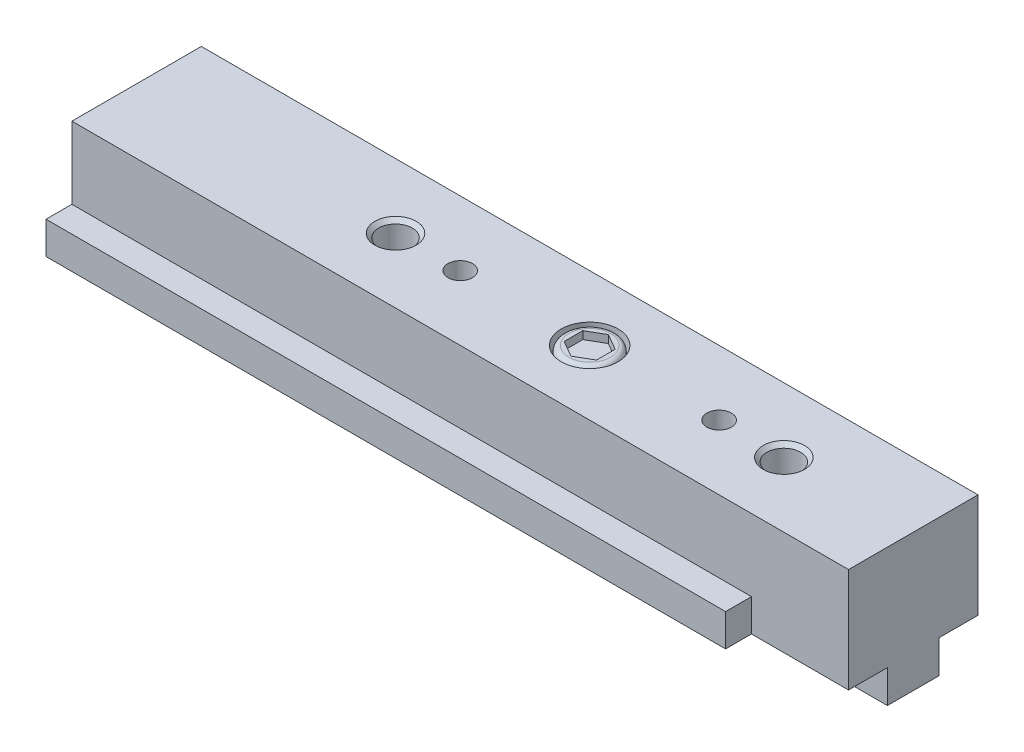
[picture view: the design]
ISO-10303-21;
HEADER;
FILE_DESCRIPTION(('STEP AP214'),'2;1');
FILE_NAME('part.step','',(''),(''),'','','');
FILE_SCHEMA(('AUTOMOTIVE_DESIGN { 1 0 10303 214 1 1 1 1 }'));
ENDSEC;
DATA;
#1=APPLICATION_CONTEXT('core data for automotive mechanical design processes');
#2=APPLICATION_PROTOCOL_DEFINITION('international standard','automotive_design',2000,#1);
#3=PRODUCT_CONTEXT('',#1,'mechanical');
#4=PRODUCT('Part','Part','',(#3));
#5=PRODUCT_RELATED_PRODUCT_CATEGORY('part','',(#4));
#6=PRODUCT_DEFINITION_FORMATION('','',#4);
#7=PRODUCT_DEFINITION_CONTEXT('part definition',#1,'design');
#8=PRODUCT_DEFINITION('design','',#6,#7);
#9=PRODUCT_DEFINITION_SHAPE('','',#8);
#10=(LENGTH_UNIT() NAMED_UNIT(*) SI_UNIT(.MILLI.,.METRE.));
#11=(NAMED_UNIT(*) PLANE_ANGLE_UNIT() SI_UNIT($,.RADIAN.));
#12=(NAMED_UNIT(*) SI_UNIT($,.STERADIAN.) SOLID_ANGLE_UNIT());
#13=UNCERTAINTY_MEASURE_WITH_UNIT(LENGTH_MEASURE(1.E-05),#10,'distance_accuracy_value','');
#14=(GEOMETRIC_REPRESENTATION_CONTEXT(3) GLOBAL_UNCERTAINTY_ASSIGNED_CONTEXT((#13)) GLOBAL_UNIT_ASSIGNED_CONTEXT((#10,
#11,#12)) REPRESENTATION_CONTEXT('',''));
#15=CARTESIAN_POINT('',(0.,0.,0.));
#16=DIRECTION('',(0.,0.,1.));
#17=DIRECTION('',(1.,0.,0.));
#18=AXIS2_PLACEMENT_3D('',#15,#16,#17);
#19=CARTESIAN_POINT('',(44.45,11.938,0.));
#20=DIRECTION('',(0.,1.,0.));
#21=DIRECTION('',(0.,0.,1.));
#22=AXIS2_PLACEMENT_3D('',#19,#20,#21);
#23=PLANE('',#22);
#24=CARTESIAN_POINT('',(44.45,11.938,0.));
#25=DIRECTION('',(0.,1.,0.));
#26=DIRECTION('',(0.,0.,1.));
#27=AXIS2_PLACEMENT_3D('',#24,#25,#26);
#28=CIRCLE('',#27,2.794);
#29=CARTESIAN_POINT('',(44.45,11.938,2.794));
#30=VERTEX_POINT('',#29);
#31=EDGE_CURVE('E242',#30,#30,#28,.T.);
#32=ORIENTED_EDGE('',*,*,#31,.T.);
#33=EDGE_LOOP('',(#32));
#34=FACE_BOUND('',#33,.T.);
#35=CARTESIAN_POINT('',(44.45,11.938,0.));
#36=DIRECTION('',(0.,1.,0.));
#37=DIRECTION('',(0.,0.,1.));
#38=AXIS2_PLACEMENT_3D('',#35,#36,#37);
#39=CIRCLE('',#38,2.54);
#40=CARTESIAN_POINT('',(44.45,11.938,2.54));
#41=VERTEX_POINT('',#40);
#42=EDGE_CURVE('E225',#41,#41,#39,.T.);
#43=ORIENTED_EDGE('',*,*,#42,.F.);
#44=EDGE_LOOP('',(#43));
#45=FACE_BOUND('',#44,.T.);
#46=ADVANCED_FACE('F33',(#34,#45),#23,.T.);
#47=CARTESIAN_POINT('',(66.675,13.462,-6.35));
#48=DIRECTION('',(0.,-1.,0.));
#49=DIRECTION('',(0.,0.,-1.));
#50=AXIS2_PLACEMENT_3D('',#47,#48,#49);
#51=PLANE('',#50);
#52=CARTESIAN_POINT('',(44.45,13.462,0.));
#53=DIRECTION('',(0.,1.,0.));
#54=DIRECTION('',(0.,0.,1.));
#55=AXIS2_PLACEMENT_3D('',#52,#53,#54);
#56=CIRCLE('',#55,2.794);
#57=CARTESIAN_POINT('',(44.45,13.462,2.794));
#58=VERTEX_POINT('',#57);
#59=EDGE_CURVE('E241',#58,#58,#56,.T.);
#60=ORIENTED_EDGE('',*,*,#59,.F.);
#61=EDGE_LOOP('',(#60));
#62=FACE_BOUND('',#61,.T.);
#63=CARTESIAN_POINT('',(31.75,13.462,0.));
#64=DIRECTION('',(0.,1.,0.));
#65=DIRECTION('',(0.,0.,1.));
#66=AXIS2_PLACEMENT_3D('',#63,#64,#65);
#67=CIRCLE('',#66,1.20269);
#68=CARTESIAN_POINT('',(31.75,13.462,1.20269));
#69=VERTEX_POINT('',#68);
#70=EDGE_CURVE('E245',#69,#69,#67,.T.);
#71=ORIENTED_EDGE('',*,*,#70,.F.);
#72=EDGE_LOOP('',(#71));
#73=FACE_BOUND('',#72,.T.);
#74=CARTESIAN_POINT('',(57.15,13.462,0.));
#75=DIRECTION('',(0.,1.,0.));
#76=DIRECTION('',(0.,0.,1.));
#77=AXIS2_PLACEMENT_3D('',#74,#75,#76);
#78=CIRCLE('',#77,1.20269);
#79=CARTESIAN_POINT('',(57.15,13.462,1.20269));
#80=VERTEX_POINT('',#79);
#81=EDGE_CURVE('E251',#80,#80,#78,.T.);
#82=ORIENTED_EDGE('',*,*,#81,.F.);
#83=EDGE_LOOP('',(#82));
#84=FACE_BOUND('',#83,.T.);
#85=CARTESIAN_POINT('',(63.5,13.462,0.));
#86=DIRECTION('',(0.,1.,0.));
#87=DIRECTION('',(0.,0.,1.));
#88=AXIS2_PLACEMENT_3D('',#85,#86,#87);
#89=CIRCLE('',#88,2.032);
#90=CARTESIAN_POINT('',(63.5,13.462,2.032));
#91=VERTEX_POINT('',#90);
#92=EDGE_CURVE('E274',#91,#91,#89,.T.);
#93=ORIENTED_EDGE('',*,*,#92,.F.);
#94=EDGE_LOOP('',(#93));
#95=FACE_BOUND('',#94,.T.);
#96=DIRECTION('',(0.,0.,1.));
#97=VECTOR('',#96,1.);
#98=CARTESIAN_POINT('',(0.,13.462,-6.35));
#99=LINE('',#98,#97);
#100=CARTESIAN_POINT('',(0.,13.462,-6.35));
#101=VERTEX_POINT('',#100);
#102=CARTESIAN_POINT('',(0.,13.462,6.35));
#103=VERTEX_POINT('',#102);
#104=EDGE_CURVE('E400',#101,#103,#99,.T.);
#105=ORIENTED_EDGE('',*,*,#104,.T.);
#106=DIRECTION('',(-1.,0.,0.));
#107=VECTOR('',#106,1.);
#108=CARTESIAN_POINT('',(66.675,13.462,6.35));
#109=LINE('',#108,#107);
#110=CARTESIAN_POINT('',(76.2,13.462,6.35));
#111=VERTEX_POINT('',#110);
#112=EDGE_CURVE('E336',#111,#103,#109,.T.);
#113=ORIENTED_EDGE('',*,*,#112,.F.);
#114=DIRECTION('',(0.,0.,1.));
#115=VECTOR('',#114,1.);
#116=CARTESIAN_POINT('',(76.2,13.462,-6.35));
#117=LINE('',#116,#115);
#118=CARTESIAN_POINT('',(76.2,13.462,-6.35));
#119=VERTEX_POINT('',#118);
#120=EDGE_CURVE('E297',#119,#111,#117,.T.);
#121=ORIENTED_EDGE('',*,*,#120,.F.);
#122=DIRECTION('',(-1.,0.,0.));
#123=VECTOR('',#122,1.);
#124=CARTESIAN_POINT('',(66.675,13.462,-6.35));
#125=LINE('',#124,#123);
#126=EDGE_CURVE('E320',#119,#101,#125,.T.);
#127=ORIENTED_EDGE('',*,*,#126,.T.);
#128=EDGE_LOOP('',(#105,#113,#121,#127));
#129=FACE_BOUND('',#128,.T.);
#130=CARTESIAN_POINT('',(25.4,13.462,0.));
#131=DIRECTION('',(0.,1.,0.));
#132=DIRECTION('',(0.,0.,1.));
#133=AXIS2_PLACEMENT_3D('',#130,#131,#132);
#134=CIRCLE('',#133,2.032);
#135=CARTESIAN_POINT('',(25.4,13.462,2.032));
#136=VERTEX_POINT('',#135);
#137=EDGE_CURVE('E265',#136,#136,#134,.T.);
#138=ORIENTED_EDGE('',*,*,#137,.F.);
#139=EDGE_LOOP('',(#138));
#140=FACE_BOUND('',#139,.T.);
#141=ADVANCED_FACE('F428',(#62,#73,#84,#95,#129,#140),#51,.F.);
#142=CARTESIAN_POINT('',(66.675,3.2258,8.89));
#143=DIRECTION('',(1.,0.,0.));
#144=DIRECTION('',(0.,0.,-1.));
#145=AXIS2_PLACEMENT_3D('',#142,#143,#144);
#146=PLANE('',#145);
#147=DIRECTION('',(0.,-1.,0.));
#148=VECTOR('',#147,1.);
#149=CARTESIAN_POINT('',(66.675,13.462,6.35));
#150=LINE('',#149,#148);
#151=CARTESIAN_POINT('',(66.675,6.4008,6.35));
#152=VERTEX_POINT('',#151);
#153=CARTESIAN_POINT('',(66.675,3.2258,6.35));
#154=VERTEX_POINT('',#153);
#155=EDGE_CURVE('E11',#152,#154,#150,.T.);
#156=ORIENTED_EDGE('',*,*,#155,.F.);
#157=DIRECTION('',(0.,0.,1.));
#158=VECTOR('',#157,1.);
#159=CARTESIAN_POINT('',(66.675,6.4008,6.35));
#160=LINE('',#159,#158);
#161=CARTESIAN_POINT('',(66.675,6.4008,8.89));
#162=VERTEX_POINT('',#161);
#163=EDGE_CURVE('E312',#152,#162,#160,.T.);
#164=ORIENTED_EDGE('',*,*,#163,.T.);
#165=DIRECTION('',(0.,-1.,0.));
#166=VECTOR('',#165,1.);
#167=CARTESIAN_POINT('',(66.675,6.4008,8.89));
#168=LINE('',#167,#166);
#169=CARTESIAN_POINT('',(66.675,3.2258,8.89));
#170=VERTEX_POINT('',#169);
#171=EDGE_CURVE('E377',#162,#170,#168,.T.);
#172=ORIENTED_EDGE('',*,*,#171,.T.);
#173=DIRECTION('',(0.,0.,-1.));
#174=VECTOR('',#173,1.);
#175=CARTESIAN_POINT('',(66.675,3.2258,8.89));
#176=LINE('',#175,#174);
#177=EDGE_CURVE('E375',#170,#154,#176,.T.);
#178=ORIENTED_EDGE('',*,*,#177,.T.);
#179=EDGE_LOOP('',(#156,#164,#172,#178));
#180=FACE_BOUND('',#179,.T.);
#181=ADVANCED_FACE('F408',(#180),#146,.T.);
#182=CARTESIAN_POINT('',(66.675,6.4008,8.89));
#183=DIRECTION('',(0.,0.,-1.));
#184=DIRECTION('',(-1.,0.,0.));
#185=AXIS2_PLACEMENT_3D('',#182,#183,#184);
#186=PLANE('',#185);
#187=DIRECTION('',(0.,-1.,0.));
#188=VECTOR('',#187,1.);
#189=CARTESIAN_POINT('',(0.,6.4008,8.89));
#190=LINE('',#189,#188);
#191=CARTESIAN_POINT('',(0.,6.4008,8.89));
#192=VERTEX_POINT('',#191);
#193=CARTESIAN_POINT('',(0.,3.2258,8.89));
#194=VERTEX_POINT('',#193);
#195=EDGE_CURVE('E330',#192,#194,#190,.T.);
#196=ORIENTED_EDGE('',*,*,#195,.T.);
#197=DIRECTION('',(-1.,0.,0.));
#198=VECTOR('',#197,1.);
#199=CARTESIAN_POINT('',(66.675,3.2258,8.89));
#200=LINE('',#199,#198);
#201=EDGE_CURVE('E42',#170,#194,#200,.T.);
#202=ORIENTED_EDGE('',*,*,#201,.F.);
#203=ORIENTED_EDGE('',*,*,#171,.F.);
#204=DIRECTION('',(-1.,0.,0.));
#205=VECTOR('',#204,1.);
#206=CARTESIAN_POINT('',(66.675,6.4008,8.89));
#207=LINE('',#206,#205);
#208=EDGE_CURVE('E337',#162,#192,#207,.T.);
#209=ORIENTED_EDGE('',*,*,#208,.T.);
#210=EDGE_LOOP('',(#196,#202,#203,#209));
#211=FACE_BOUND('',#210,.T.);
#212=ADVANCED_FACE('F35',(#211),#186,.F.);
#213=CARTESIAN_POINT('',(66.675,3.2258,8.89));
#214=DIRECTION('',(0.,1.,0.));
#215=DIRECTION('',(0.,0.,1.));
#216=AXIS2_PLACEMENT_3D('',#213,#214,#215);
#217=PLANE('',#216);
#218=DIRECTION('',(0.,0.,-1.));
#219=VECTOR('',#218,1.);
#220=CARTESIAN_POINT('',(0.,3.2258,8.89));
#221=LINE('',#220,#219);
#222=CARTESIAN_POINT('',(0.,3.2258,2.54));
#223=VERTEX_POINT('',#222);
#224=EDGE_CURVE('E384',#194,#223,#221,.T.);
#225=ORIENTED_EDGE('',*,*,#224,.T.);
#226=DIRECTION('',(-1.,0.,0.));
#227=VECTOR('',#226,1.);
#228=CARTESIAN_POINT('',(66.675,3.2258,2.54));
#229=LINE('',#228,#227);
#230=CARTESIAN_POINT('',(76.2,3.2258,2.54));
#231=VERTEX_POINT('',#230);
#232=EDGE_CURVE('E371',#231,#223,#229,.T.);
#233=ORIENTED_EDGE('',*,*,#232,.F.);
#234=DIRECTION('',(0.,0.,-1.));
#235=VECTOR('',#234,1.);
#236=CARTESIAN_POINT('',(76.2,3.2258,6.35));
#237=LINE('',#236,#235);
#238=CARTESIAN_POINT('',(76.2,3.2258,6.35));
#239=VERTEX_POINT('',#238);
#240=EDGE_CURVE('E280',#239,#231,#237,.T.);
#241=ORIENTED_EDGE('',*,*,#240,.F.);
#242=DIRECTION('',(-1.,0.,0.));
#243=VECTOR('',#242,1.);
#244=CARTESIAN_POINT('',(76.2,3.2258,6.35));
#245=LINE('',#244,#243);
#246=EDGE_CURVE('E325',#239,#154,#245,.T.);
#247=ORIENTED_EDGE('',*,*,#246,.T.);
#248=ORIENTED_EDGE('',*,*,#177,.F.);
#249=ORIENTED_EDGE('',*,*,#201,.T.);
#250=EDGE_LOOP('',(#225,#233,#241,#247,#248,#249));
#251=FACE_BOUND('',#250,.T.);
#252=ADVANCED_FACE('F410',(#251),#217,.F.);
#253=CARTESIAN_POINT('',(66.675,3.2258,2.54));
#254=DIRECTION('',(0.,0.,-1.));
#255=DIRECTION('',(-1.,0.,0.));
#256=AXIS2_PLACEMENT_3D('',#253,#254,#255);
#257=PLANE('',#256);
#258=DIRECTION('',(0.,-1.,0.));
#259=VECTOR('',#258,1.);
#260=CARTESIAN_POINT('',(0.,3.2258,2.54));
#261=LINE('',#260,#259);
#262=CARTESIAN_POINT('',(0.,0.,2.54));
#263=VERTEX_POINT('',#262);
#264=EDGE_CURVE('E386',#223,#263,#261,.T.);
#265=ORIENTED_EDGE('',*,*,#264,.T.);
#266=DIRECTION('',(-1.,0.,0.));
#267=VECTOR('',#266,1.);
#268=CARTESIAN_POINT('',(66.675,0.,2.54));
#269=LINE('',#268,#267);
#270=CARTESIAN_POINT('',(76.2,0.,2.54));
#271=VERTEX_POINT('',#270);
#272=EDGE_CURVE('E368',#271,#263,#269,.T.);
#273=ORIENTED_EDGE('',*,*,#272,.F.);
#274=DIRECTION('',(0.,-1.,0.));
#275=VECTOR('',#274,1.);
#276=CARTESIAN_POINT('',(76.2,3.2258,2.54));
#277=LINE('',#276,#275);
#278=EDGE_CURVE('E283',#231,#271,#277,.T.);
#279=ORIENTED_EDGE('',*,*,#278,.F.);
#280=ORIENTED_EDGE('',*,*,#232,.T.);
#281=EDGE_LOOP('',(#265,#273,#279,#280));
#282=FACE_BOUND('',#281,.T.);
#283=ADVANCED_FACE('F496',(#282),#257,.F.);
#284=CARTESIAN_POINT('',(66.675,0.,2.54));
#285=DIRECTION('',(0.,1.,0.));
#286=DIRECTION('',(0.,0.,1.));
#287=AXIS2_PLACEMENT_3D('',#284,#285,#286);
#288=PLANE('',#287);
#289=DIRECTION('',(0.,0.,-1.));
#290=VECTOR('',#289,1.);
#291=CARTESIAN_POINT('',(0.,0.,2.54));
#292=LINE('',#291,#290);
#293=CARTESIAN_POINT('',(0.,0.,-2.54));
#294=VERTEX_POINT('',#293);
#295=EDGE_CURVE('E388',#263,#294,#292,.T.);
#296=ORIENTED_EDGE('',*,*,#295,.T.);
#297=DIRECTION('',(-1.,0.,0.));
#298=VECTOR('',#297,1.);
#299=CARTESIAN_POINT('',(66.675,0.,-2.54));
#300=LINE('',#299,#298);
#301=CARTESIAN_POINT('',(76.2,0.,-2.54));
#302=VERTEX_POINT('',#301);
#303=EDGE_CURVE('E365',#302,#294,#300,.T.);
#304=ORIENTED_EDGE('',*,*,#303,.F.);
#305=DIRECTION('',(0.,0.,-1.));
#306=VECTOR('',#305,1.);
#307=CARTESIAN_POINT('',(76.2,0.,2.54));
#308=LINE('',#307,#306);
#309=EDGE_CURVE('E286',#271,#302,#308,.T.);
#310=ORIENTED_EDGE('',*,*,#309,.F.);
#311=ORIENTED_EDGE('',*,*,#272,.T.);
#312=EDGE_LOOP('',(#296,#304,#310,#311));
#313=FACE_BOUND('',#312,.T.);
#314=ADVANCED_FACE('F500',(#313),#288,.F.);
#315=CARTESIAN_POINT('',(66.675,0.,-2.54));
#316=DIRECTION('',(0.,0.,1.));
#317=DIRECTION('',(1.,0.,0.));
#318=AXIS2_PLACEMENT_3D('',#315,#316,#317);
#319=PLANE('',#318);
#320=DIRECTION('',(0.,1.,0.));
#321=VECTOR('',#320,1.);
#322=CARTESIAN_POINT('',(0.,0.,-2.54));
#323=LINE('',#322,#321);
#324=CARTESIAN_POINT('',(0.,3.2258,-2.54));
#325=VERTEX_POINT('',#324);
#326=EDGE_CURVE('E390',#294,#325,#323,.T.);
#327=ORIENTED_EDGE('',*,*,#326,.T.);
#328=DIRECTION('',(-1.,0.,0.));
#329=VECTOR('',#328,1.);
#330=CARTESIAN_POINT('',(66.675,3.2258,-2.54));
#331=LINE('',#330,#329);
#332=CARTESIAN_POINT('',(76.2,3.2258,-2.54));
#333=VERTEX_POINT('',#332);
#334=EDGE_CURVE('E362',#333,#325,#331,.T.);
#335=ORIENTED_EDGE('',*,*,#334,.F.);
#336=DIRECTION('',(0.,1.,0.));
#337=VECTOR('',#336,1.);
#338=CARTESIAN_POINT('',(76.2,0.,-2.54));
#339=LINE('',#338,#337);
#340=EDGE_CURVE('E289',#302,#333,#339,.T.);
#341=ORIENTED_EDGE('',*,*,#340,.F.);
#342=ORIENTED_EDGE('',*,*,#303,.T.);
#343=EDGE_LOOP('',(#327,#335,#341,#342));
#344=FACE_BOUND('',#343,.T.);
#345=ADVANCED_FACE('F504',(#344),#319,.F.);
#346=CARTESIAN_POINT('',(66.675,3.2258,-2.54));
#347=DIRECTION('',(0.,1.,0.));
#348=DIRECTION('',(0.,0.,1.));
#349=AXIS2_PLACEMENT_3D('',#346,#347,#348);
#350=PLANE('',#349);
#351=DIRECTION('',(0.,0.,-1.));
#352=VECTOR('',#351,1.);
#353=CARTESIAN_POINT('',(0.,3.2258,-2.54));
#354=LINE('',#353,#352);
#355=CARTESIAN_POINT('',(0.,3.2258,-8.89));
#356=VERTEX_POINT('',#355);
#357=EDGE_CURVE('E392',#325,#356,#354,.T.);
#358=ORIENTED_EDGE('',*,*,#357,.T.);
#359=DIRECTION('',(-1.,0.,0.));
#360=VECTOR('',#359,1.);
#361=CARTESIAN_POINT('',(66.675,3.2258,-8.89));
#362=LINE('',#361,#360);
#363=CARTESIAN_POINT('',(66.675,3.2258,-8.89));
#364=VERTEX_POINT('',#363);
#365=EDGE_CURVE('E359',#364,#356,#362,.T.);
#366=ORIENTED_EDGE('',*,*,#365,.F.);
#367=DIRECTION('',(0.,0.,-1.));
#368=VECTOR('',#367,1.);
#369=CARTESIAN_POINT('',(66.675,3.2258,-2.54));
#370=LINE('',#369,#368);
#371=CARTESIAN_POINT('',(66.675,3.2258,-6.35));
#372=VERTEX_POINT('',#371);
#373=EDGE_CURVE('E307',#372,#364,#370,.T.);
#374=ORIENTED_EDGE('',*,*,#373,.F.);
#375=DIRECTION('',(-1.,0.,0.));
#376=VECTOR('',#375,1.);
#377=CARTESIAN_POINT('',(76.2,3.2258,-6.35));
#378=LINE('',#377,#376);
#379=CARTESIAN_POINT('',(76.2,3.2258,-6.35));
#380=VERTEX_POINT('',#379);
#381=EDGE_CURVE('E300',#380,#372,#378,.T.);
#382=ORIENTED_EDGE('',*,*,#381,.F.);
#383=DIRECTION('',(0.,0.,-1.));
#384=VECTOR('',#383,1.);
#385=CARTESIAN_POINT('',(76.2,3.2258,-2.54));
#386=LINE('',#385,#384);
#387=EDGE_CURVE('E292',#333,#380,#386,.T.);
#388=ORIENTED_EDGE('',*,*,#387,.F.);
#389=ORIENTED_EDGE('',*,*,#334,.T.);
#390=EDGE_LOOP('',(#358,#366,#374,#382,#388,#389));
#391=FACE_BOUND('',#390,.T.);
#392=ADVANCED_FACE('F507',(#391),#350,.F.);
#393=CARTESIAN_POINT('',(66.675,3.2258,-8.89));
#394=DIRECTION('',(0.,0.,1.));
#395=DIRECTION('',(1.,0.,0.));
#396=AXIS2_PLACEMENT_3D('',#393,#394,#395);
#397=PLANE('',#396);
#398=DIRECTION('',(0.,1.,0.));
#399=VECTOR('',#398,1.);
#400=CARTESIAN_POINT('',(0.,3.2258,-8.89));
#401=LINE('',#400,#399);
#402=CARTESIAN_POINT('',(0.,6.4008,-8.89));
#403=VERTEX_POINT('',#402);
#404=EDGE_CURVE('E394',#356,#403,#401,.T.);
#405=ORIENTED_EDGE('',*,*,#404,.T.);
#406=DIRECTION('',(-1.,0.,0.));
#407=VECTOR('',#406,1.);
#408=CARTESIAN_POINT('',(66.675,6.4008,-8.89));
#409=LINE('',#408,#407);
#410=CARTESIAN_POINT('',(66.675,6.4008,-8.89));
#411=VERTEX_POINT('',#410);
#412=EDGE_CURVE('E319',#411,#403,#409,.T.);
#413=ORIENTED_EDGE('',*,*,#412,.F.);
#414=DIRECTION('',(0.,1.,0.));
#415=VECTOR('',#414,1.);
#416=CARTESIAN_POINT('',(66.675,3.2258,-8.89));
#417=LINE('',#416,#415);
#418=EDGE_CURVE('E313',#364,#411,#417,.T.);
#419=ORIENTED_EDGE('',*,*,#418,.F.);
#420=ORIENTED_EDGE('',*,*,#365,.T.);
#421=EDGE_LOOP('',(#405,#413,#419,#420));
#422=FACE_BOUND('',#421,.T.);
#423=ADVANCED_FACE('F515',(#422),#397,.F.);
#424=CARTESIAN_POINT('',(66.675,6.4008,-8.89));
#425=DIRECTION('',(0.,-1.,0.));
#426=DIRECTION('',(0.,0.,-1.));
#427=AXIS2_PLACEMENT_3D('',#424,#425,#426);
#428=PLANE('',#427);
#429=DIRECTION('',(0.,0.,1.));
#430=VECTOR('',#429,1.);
#431=CARTESIAN_POINT('',(0.,6.4008,-8.89));
#432=LINE('',#431,#430);
#433=CARTESIAN_POINT('',(0.,6.4008,-6.35));
#434=VERTEX_POINT('',#433);
#435=EDGE_CURVE('E396',#403,#434,#432,.T.);
#436=ORIENTED_EDGE('',*,*,#435,.T.);
#437=DIRECTION('',(-1.,0.,0.));
#438=VECTOR('',#437,1.);
#439=CARTESIAN_POINT('',(66.675,6.4008,-6.35));
#440=LINE('',#439,#438);
#441=CARTESIAN_POINT('',(66.675,6.4008,-6.35));
#442=VERTEX_POINT('',#441);
#443=EDGE_CURVE('E316',#442,#434,#440,.T.);
#444=ORIENTED_EDGE('',*,*,#443,.F.);
#445=DIRECTION('',(0.,0.,1.));
#446=VECTOR('',#445,1.);
#447=CARTESIAN_POINT('',(66.675,6.4008,-8.89));
#448=LINE('',#447,#446);
#449=EDGE_CURVE('E310',#411,#442,#448,.T.);
#450=ORIENTED_EDGE('',*,*,#449,.F.);
#451=ORIENTED_EDGE('',*,*,#412,.T.);
#452=EDGE_LOOP('',(#436,#444,#450,#451));
#453=FACE_BOUND('',#452,.T.);
#454=ADVANCED_FACE('F519',(#453),#428,.F.);
#455=CARTESIAN_POINT('',(66.675,6.4008,-6.35));
#456=DIRECTION('',(0.,0.,1.));
#457=DIRECTION('',(1.,0.,0.));
#458=AXIS2_PLACEMENT_3D('',#455,#456,#457);
#459=PLANE('',#458);
#460=DIRECTION('',(0.,1.,0.));
#461=VECTOR('',#460,1.);
#462=CARTESIAN_POINT('',(0.,6.4008,-6.35));
#463=LINE('',#462,#461);
#464=EDGE_CURVE('E398',#434,#101,#463,.T.);
#465=ORIENTED_EDGE('',*,*,#464,.T.);
#466=ORIENTED_EDGE('',*,*,#126,.F.);
#467=DIRECTION('',(0.,1.,0.));
#468=VECTOR('',#467,1.);
#469=CARTESIAN_POINT('',(76.2,3.2258,-6.35));
#470=LINE('',#469,#468);
#471=EDGE_CURVE('E294',#380,#119,#470,.T.);
#472=ORIENTED_EDGE('',*,*,#471,.F.);
#473=ORIENTED_EDGE('',*,*,#381,.T.);
#474=DIRECTION('',(0.,1.,0.));
#475=VECTOR('',#474,1.);
#476=CARTESIAN_POINT('',(66.675,3.2258,-6.35));
#477=LINE('',#476,#475);
#478=EDGE_CURVE('E58',#372,#442,#477,.T.);
#479=ORIENTED_EDGE('',*,*,#478,.T.);
#480=ORIENTED_EDGE('',*,*,#443,.T.);
#481=EDGE_LOOP('',(#465,#466,#472,#473,#479,#480));
#482=FACE_BOUND('',#481,.T.);
#483=ADVANCED_FACE('F424',(#482),#459,.F.);
#484=CARTESIAN_POINT('',(66.675,13.462,6.35));
#485=DIRECTION('',(0.,0.,-1.));
#486=DIRECTION('',(-1.,0.,0.));
#487=AXIS2_PLACEMENT_3D('',#484,#485,#486);
#488=PLANE('',#487);
#489=DIRECTION('',(0.,-1.,0.));
#490=VECTOR('',#489,1.);
#491=CARTESIAN_POINT('',(0.,13.462,6.35));
#492=LINE('',#491,#490);
#493=CARTESIAN_POINT('',(0.,6.4008,6.35));
#494=VERTEX_POINT('',#493);
#495=EDGE_CURVE('E401',#103,#494,#492,.T.);
#496=ORIENTED_EDGE('',*,*,#495,.T.);
#497=DIRECTION('',(-1.,0.,0.));
#498=VECTOR('',#497,1.);
#499=CARTESIAN_POINT('',(66.675,6.4008,6.35));
#500=LINE('',#499,#498);
#501=EDGE_CURVE('E333',#152,#494,#500,.T.);
#502=ORIENTED_EDGE('',*,*,#501,.F.);
#503=ORIENTED_EDGE('',*,*,#155,.T.);
#504=ORIENTED_EDGE('',*,*,#246,.F.);
#505=DIRECTION('',(0.,-1.,0.));
#506=VECTOR('',#505,1.);
#507=CARTESIAN_POINT('',(76.2,13.462,6.35));
#508=LINE('',#507,#506);
#509=EDGE_CURVE('E277',#111,#239,#508,.T.);
#510=ORIENTED_EDGE('',*,*,#509,.F.);
#511=ORIENTED_EDGE('',*,*,#112,.T.);
#512=EDGE_LOOP('',(#496,#502,#503,#504,#510,#511));
#513=FACE_BOUND('',#512,.T.);
#514=ADVANCED_FACE('F413',(#513),#488,.F.);
#515=CARTESIAN_POINT('',(66.675,6.4008,6.35));
#516=DIRECTION('',(0.,-1.,0.));
#517=DIRECTION('',(0.,0.,-1.));
#518=AXIS2_PLACEMENT_3D('',#515,#516,#517);
#519=PLANE('',#518);
#520=DIRECTION('',(0.,0.,1.));
#521=VECTOR('',#520,1.);
#522=CARTESIAN_POINT('',(0.,6.4008,6.35));
#523=LINE('',#522,#521);
#524=EDGE_CURVE('E351',#494,#192,#523,.T.);
#525=ORIENTED_EDGE('',*,*,#524,.T.);
#526=ORIENTED_EDGE('',*,*,#208,.F.);
#527=ORIENTED_EDGE('',*,*,#163,.F.);
#528=ORIENTED_EDGE('',*,*,#501,.T.);
#529=EDGE_LOOP('',(#525,#526,#527,#528));
#530=FACE_BOUND('',#529,.T.);
#531=ADVANCED_FACE('F414',(#530),#519,.F.);
#532=ORIENTED_EDGE('',*,*,#478,.F.);
#533=ORIENTED_EDGE('',*,*,#373,.T.);
#534=ORIENTED_EDGE('',*,*,#418,.T.);
#535=ORIENTED_EDGE('',*,*,#449,.T.);
#536=EDGE_LOOP('',(#532,#533,#534,#535));
#537=FACE_BOUND('',#536,.T.);
#538=ADVANCED_FACE('F416',(#537),#146,.T.);
#539=CARTESIAN_POINT('',(0.,3.2258,8.89));
#540=DIRECTION('',(1.,0.,0.));
#541=DIRECTION('',(0.,0.,-1.));
#542=AXIS2_PLACEMENT_3D('',#539,#540,#541);
#543=PLANE('',#542);
#544=ORIENTED_EDGE('',*,*,#195,.F.);
#545=ORIENTED_EDGE('',*,*,#524,.F.);
#546=ORIENTED_EDGE('',*,*,#495,.F.);
#547=ORIENTED_EDGE('',*,*,#104,.F.);
#548=ORIENTED_EDGE('',*,*,#464,.F.);
#549=ORIENTED_EDGE('',*,*,#435,.F.);
#550=ORIENTED_EDGE('',*,*,#404,.F.);
#551=ORIENTED_EDGE('',*,*,#357,.F.);
#552=ORIENTED_EDGE('',*,*,#326,.F.);
#553=ORIENTED_EDGE('',*,*,#295,.F.);
#554=ORIENTED_EDGE('',*,*,#264,.F.);
#555=ORIENTED_EDGE('',*,*,#224,.F.);
#556=EDGE_LOOP('',(#544,#545,#546,#547,#548,#549,#550,#551,#552,#553,#554,#555));
#557=FACE_BOUND('',#556,.T.);
#558=ADVANCED_FACE('F422',(#557),#543,.F.);
#559=CARTESIAN_POINT('',(76.2,3.2258,6.35));
#560=DIRECTION('',(1.,0.,0.));
#561=DIRECTION('',(0.,0.,-1.));
#562=AXIS2_PLACEMENT_3D('',#559,#560,#561);
#563=PLANE('',#562);
#564=ORIENTED_EDGE('',*,*,#509,.T.);
#565=ORIENTED_EDGE('',*,*,#240,.T.);
#566=ORIENTED_EDGE('',*,*,#278,.T.);
#567=ORIENTED_EDGE('',*,*,#309,.T.);
#568=ORIENTED_EDGE('',*,*,#340,.T.);
#569=ORIENTED_EDGE('',*,*,#387,.T.);
#570=ORIENTED_EDGE('',*,*,#471,.T.);
#571=ORIENTED_EDGE('',*,*,#120,.T.);
#572=EDGE_LOOP('',(#564,#565,#566,#567,#568,#569,#570,#571));
#573=FACE_BOUND('',#572,.T.);
#574=ADVANCED_FACE('F484',(#573),#563,.T.);
#575=CARTESIAN_POINT('',(63.5,13.081,0.));
#576=DIRECTION('',(0.,1.,0.));
#577=DIRECTION('',(0.,0.,1.));
#578=AXIS2_PLACEMENT_3D('',#575,#576,#577);
#579=CONICAL_SURFACE('',#578,1.651,0.785398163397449);
#580=ORIENTED_EDGE('',*,*,#92,.T.);
#581=EDGE_LOOP('',(#580));
#582=FACE_BOUND('',#581,.T.);
#583=CARTESIAN_POINT('',(63.5,13.081,0.));
#584=DIRECTION('',(0.,1.,0.));
#585=DIRECTION('',(0.,0.,1.));
#586=AXIS2_PLACEMENT_3D('',#583,#584,#585);
#587=CIRCLE('',#586,1.651);
#588=CARTESIAN_POINT('',(63.5,13.081,1.651));
#589=VERTEX_POINT('',#588);
#590=EDGE_CURVE('E271',#589,#589,#587,.T.);
#591=ORIENTED_EDGE('',*,*,#590,.F.);
#592=EDGE_LOOP('',(#591));
#593=FACE_BOUND('',#592,.T.);
#594=ADVANCED_FACE('F480',(#582,#593),#579,.F.);
#595=CARTESIAN_POINT('',(63.5,5.207,0.));
#596=DIRECTION('',(0.,1.,0.));
#597=DIRECTION('',(0.,0.,1.));
#598=AXIS2_PLACEMENT_3D('',#595,#596,#597);
#599=CYLINDRICAL_SURFACE('',#598,1.651);
#600=ORIENTED_EDGE('',*,*,#590,.T.);
#601=EDGE_LOOP('',(#600));
#602=FACE_BOUND('',#601,.T.);
#603=CARTESIAN_POINT('',(63.5,6.1602052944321,0.));
#604=DIRECTION('',(0.,1.,0.));
#605=DIRECTION('',(0.,0.,1.));
#606=AXIS2_PLACEMENT_3D('',#603,#604,#605);
#607=CIRCLE('',#606,1.651);
#608=CARTESIAN_POINT('',(63.5,6.1602052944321,1.651));
#609=VERTEX_POINT('',#608);
#610=EDGE_CURVE('E268',#609,#609,#607,.T.);
#611=ORIENTED_EDGE('',*,*,#610,.F.);
#612=EDGE_LOOP('',(#611));
#613=FACE_BOUND('',#612,.T.);
#614=ADVANCED_FACE('F476',(#602,#613),#599,.F.);
#615=CARTESIAN_POINT('',(63.5,5.207,0.));
#616=DIRECTION('',(0.,1.,0.));
#617=DIRECTION('',(0.,0.,1.));
#618=AXIS2_PLACEMENT_3D('',#615,#616,#617);
#619=CONICAL_SURFACE('',#618,0.,1.04719755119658);
#620=ORIENTED_EDGE('',*,*,#610,.T.);
#621=EDGE_LOOP('',(#620));
#622=FACE_BOUND('',#621,.T.);
#623=CARTESIAN_POINT('',(63.5,5.207,0.));
#624=VERTEX_POINT('',#623);
#625=VERTEX_LOOP('',#624);
#626=FACE_BOUND('',#625,.T.);
#627=ADVANCED_FACE('F472',(#622,#626),#619,.F.);
#628=CARTESIAN_POINT('',(25.4,13.081,0.));
#629=DIRECTION('',(0.,1.,0.));
#630=DIRECTION('',(0.,0.,1.));
#631=AXIS2_PLACEMENT_3D('',#628,#629,#630);
#632=CONICAL_SURFACE('',#631,1.651,0.785398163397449);
#633=ORIENTED_EDGE('',*,*,#137,.T.);
#634=EDGE_LOOP('',(#633));
#635=FACE_BOUND('',#634,.T.);
#636=CARTESIAN_POINT('',(25.4,13.081,0.));
#637=DIRECTION('',(0.,1.,0.));
#638=DIRECTION('',(0.,0.,1.));
#639=AXIS2_PLACEMENT_3D('',#636,#637,#638);
#640=CIRCLE('',#639,1.651);
#641=CARTESIAN_POINT('',(25.4,13.081,1.651));
#642=VERTEX_POINT('',#641);
#643=EDGE_CURVE('E262',#642,#642,#640,.T.);
#644=ORIENTED_EDGE('',*,*,#643,.F.);
#645=EDGE_LOOP('',(#644));
#646=FACE_BOUND('',#645,.T.);
#647=ADVANCED_FACE('F468',(#635,#646),#632,.F.);
#648=CARTESIAN_POINT('',(25.4,7.112,0.));
#649=DIRECTION('',(0.,1.,0.));
#650=DIRECTION('',(0.,0.,1.));
#651=AXIS2_PLACEMENT_3D('',#648,#649,#650);
#652=CYLINDRICAL_SURFACE('',#651,1.651);
#653=ORIENTED_EDGE('',*,*,#643,.T.);
#654=EDGE_LOOP('',(#653));
#655=FACE_BOUND('',#654,.T.);
#656=CARTESIAN_POINT('',(25.4,8.0652052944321,0.));
#657=DIRECTION('',(0.,1.,0.));
#658=DIRECTION('',(0.,0.,1.));
#659=AXIS2_PLACEMENT_3D('',#656,#657,#658);
#660=CIRCLE('',#659,1.651);
#661=CARTESIAN_POINT('',(25.4,8.0652052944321,1.651));
#662=VERTEX_POINT('',#661);
#663=EDGE_CURVE('E257',#662,#662,#660,.T.);
#664=ORIENTED_EDGE('',*,*,#663,.F.);
#665=EDGE_LOOP('',(#664));
#666=FACE_BOUND('',#665,.T.);
#667=ADVANCED_FACE('F464',(#655,#666),#652,.F.);
#668=CARTESIAN_POINT('',(25.4,7.112,0.));
#669=DIRECTION('',(0.,1.,0.));
#670=DIRECTION('',(0.,0.,1.));
#671=AXIS2_PLACEMENT_3D('',#668,#669,#670);
#672=CONICAL_SURFACE('',#671,0.,1.04719755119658);
#673=ORIENTED_EDGE('',*,*,#663,.T.);
#674=EDGE_LOOP('',(#673));
#675=FACE_BOUND('',#674,.T.);
#676=CARTESIAN_POINT('',(25.4,7.112,0.));
#677=VERTEX_POINT('',#676);
#678=VERTEX_LOOP('',#677);
#679=FACE_BOUND('',#678,.T.);
#680=ADVANCED_FACE('F460',(#675,#679),#672,.F.);
#681=CARTESIAN_POINT('',(57.15,10.414,0.));
#682=DIRECTION('',(0.,1.,0.));
#683=DIRECTION('',(0.,0.,1.));
#684=AXIS2_PLACEMENT_3D('',#681,#682,#683);
#685=CYLINDRICAL_SURFACE('',#684,1.20269);
#686=CARTESIAN_POINT('',(57.15,10.414,0.));
#687=DIRECTION('',(0.,1.,0.));
#688=DIRECTION('',(0.,0.,1.));
#689=AXIS2_PLACEMENT_3D('',#686,#687,#688);
#690=CIRCLE('',#689,1.20269);
#691=CARTESIAN_POINT('',(57.15,10.414,1.20269));
#692=VERTEX_POINT('',#691);
#693=EDGE_CURVE('E254',#692,#692,#690,.T.);
#694=CARTESIAN_POINT('',(57.15,10.414,1.20269));
#695=CARTESIAN_POINT('',(57.15,10.44575,1.20269));
#696=CARTESIAN_POINT('',(57.15,10.4775,1.20269));
#697=CARTESIAN_POINT('',(57.15,10.541,1.20269));
#698=CARTESIAN_POINT('',(57.15,10.57275,1.20269));
#699=CARTESIAN_POINT('',(57.15,10.63625,1.20269));
#700=CARTESIAN_POINT('',(57.15,10.668,1.20269));
#701=CARTESIAN_POINT('',(57.15,10.7315,1.20269));
#702=CARTESIAN_POINT('',(57.15,10.76325,1.20269));
#703=CARTESIAN_POINT('',(57.15,10.82675,1.20269));
#704=CARTESIAN_POINT('',(57.15,10.8585,1.20269));
#705=CARTESIAN_POINT('',(57.15,10.922,1.20269));
#706=CARTESIAN_POINT('',(57.15,10.95375,1.20269));
#707=CARTESIAN_POINT('',(57.15,11.01725,1.20269));
#708=CARTESIAN_POINT('',(57.15,11.049,1.20269));
#709=CARTESIAN_POINT('',(57.15,11.1125,1.20269));
#710=CARTESIAN_POINT('',(57.15,11.14425,1.20269));
#711=CARTESIAN_POINT('',(57.15,11.20775,1.20269));
#712=CARTESIAN_POINT('',(57.15,11.2395,1.20269));
#713=CARTESIAN_POINT('',(57.15,11.303,1.20269));
#714=CARTESIAN_POINT('',(57.15,11.33475,1.20269));
#715=CARTESIAN_POINT('',(57.15,11.39825,1.20269));
#716=CARTESIAN_POINT('',(57.15,11.43,1.20269));
#717=CARTESIAN_POINT('',(57.15,11.4935,1.20269));
#718=CARTESIAN_POINT('',(57.15,11.52525,1.20269));
#719=CARTESIAN_POINT('',(57.15,11.58875,1.20269));
#720=CARTESIAN_POINT('',(57.15,11.6205,1.20269));
#721=CARTESIAN_POINT('',(57.15,11.684,1.20269));
#722=CARTESIAN_POINT('',(57.15,11.71575,1.20269));
#723=CARTESIAN_POINT('',(57.15,11.77925,1.20269));
#724=CARTESIAN_POINT('',(57.15,11.811,1.20269));
#725=CARTESIAN_POINT('',(57.15,11.8745,1.20269));
#726=CARTESIAN_POINT('',(57.15,11.90625,1.20269));
#727=CARTESIAN_POINT('',(57.15,11.96975,1.20269));
#728=CARTESIAN_POINT('',(57.15,12.0015,1.20269));
#729=CARTESIAN_POINT('',(57.15,12.065,1.20269));
#730=CARTESIAN_POINT('',(57.15,12.09675,1.20269));
#731=CARTESIAN_POINT('',(57.15,12.16025,1.20269));
#732=CARTESIAN_POINT('',(57.15,12.192,1.20269));
#733=CARTESIAN_POINT('',(57.15,12.2555,1.20269));
#734=CARTESIAN_POINT('',(57.15,12.28725,1.20269));
#735=CARTESIAN_POINT('',(57.15,12.35075,1.20269));
#736=CARTESIAN_POINT('',(57.15,12.3825,1.20269));
#737=CARTESIAN_POINT('',(57.15,12.446,1.20269));
#738=CARTESIAN_POINT('',(57.15,12.47775,1.20269));
#739=CARTESIAN_POINT('',(57.15,12.54125,1.20269));
#740=CARTESIAN_POINT('',(57.15,12.573,1.20269));
#741=CARTESIAN_POINT('',(57.15,12.6365,1.20269));
#742=CARTESIAN_POINT('',(57.15,12.66825,1.20269));
#743=CARTESIAN_POINT('',(57.15,12.73175,1.20269));
#744=CARTESIAN_POINT('',(57.15,12.7635,1.20269));
#745=CARTESIAN_POINT('',(57.15,12.827,1.20269));
#746=CARTESIAN_POINT('',(57.15,12.85875,1.20269));
#747=CARTESIAN_POINT('',(57.15,12.92225,1.20269));
#748=CARTESIAN_POINT('',(57.15,12.954,1.20269));
#749=CARTESIAN_POINT('',(57.15,13.0175,1.20269));
#750=CARTESIAN_POINT('',(57.15,13.04925,1.20269));
#751=CARTESIAN_POINT('',(57.15,13.11275,1.20269));
#752=CARTESIAN_POINT('',(57.15,13.1445,1.20269));
#753=CARTESIAN_POINT('',(57.15,13.208,1.20269));
#754=CARTESIAN_POINT('',(57.15,13.23975,1.20269));
#755=CARTESIAN_POINT('',(57.15,13.30325,1.20269));
#756=CARTESIAN_POINT('',(57.15,13.335,1.20269));
#757=CARTESIAN_POINT('',(57.15,13.3985,1.20269));
#758=CARTESIAN_POINT('',(57.15,13.43025,1.20269));
#759=CARTESIAN_POINT('',(57.15,13.462,1.20269));
#760=B_SPLINE_CURVE_WITH_KNOTS('',3,(#694,#695,#696,#697,#698,#699,#700,#701,#702,#703,#704,
#705,#706,#707,#708,#709,#710,#711,#712,#713,#714,#715,#716,#717,#718,#719,#720,#721,#722,#723,
#724,#725,#726,#727,#728,#729,#730,#731,#732,#733,#734,#735,#736,#737,#738,#739,#740,#741,#742,
#743,#744,#745,#746,#747,#748,#749,#750,#751,#752,#753,#754,#755,#756,#757,#758,#759),
.UNSPECIFIED.,.F.,.F.,(4,2,2,2,2,2,2,2,2,2,2,2,2,2,2,2,2,2,2,2,2,2,2,2,2,2,2,2,2,2,2,2,4),(0.,
0.0952499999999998,0.1905,0.28575,0.380999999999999,0.476249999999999,0.571499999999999,
0.666749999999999,0.761999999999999,0.857249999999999,0.9525,1.04775,1.143,1.23825,1.3335,
1.42875,1.524,1.61925,1.7145,1.80975,1.905,2.00025,2.0955,2.19075,2.286,2.38125,2.4765,2.57175,
2.667,2.76225,2.8575,2.95275,3.048),.UNSPECIFIED.);
#761=EDGE_CURVE('BSEAM456',#692,#80,#760,.T.);
#762=ORIENTED_EDGE('',*,*,#693,.F.);
#763=ORIENTED_EDGE('',*,*,#81,.T.);
#764=ORIENTED_EDGE('',*,*,#761,.T.);
#765=ORIENTED_EDGE('',*,*,#761,.F.);
#766=EDGE_LOOP('',(#762,#764,#763,#765));
#767=FACE_BOUND('',#766,.T.);
#768=ADVANCED_FACE('F456',(#767),#685,.F.);
#769=CARTESIAN_POINT('',(57.15,10.414,0.));
#770=DIRECTION('',(0.,1.,0.));
#771=DIRECTION('',(0.,0.,1.));
#772=AXIS2_PLACEMENT_3D('',#769,#770,#771);
#773=PLANE('',#772);
#774=ORIENTED_EDGE('',*,*,#693,.T.);
#775=EDGE_LOOP('',(#774));
#776=FACE_BOUND('',#775,.T.);
#777=ADVANCED_FACE('F452',(#776),#773,.T.);
#778=CARTESIAN_POINT('',(31.75,10.414,0.));
#779=DIRECTION('',(0.,1.,0.));
#780=DIRECTION('',(0.,0.,1.));
#781=AXIS2_PLACEMENT_3D('',#778,#779,#780);
#782=CYLINDRICAL_SURFACE('',#781,1.20269);
#783=CARTESIAN_POINT('',(31.75,10.414,0.));
#784=DIRECTION('',(0.,1.,0.));
#785=DIRECTION('',(0.,0.,1.));
#786=AXIS2_PLACEMENT_3D('',#783,#784,#785);
#787=CIRCLE('',#786,1.20269);
#788=CARTESIAN_POINT('',(31.75,10.414,1.20269));
#789=VERTEX_POINT('',#788);
#790=EDGE_CURVE('E248',#789,#789,#787,.T.);
#791=CARTESIAN_POINT('',(31.75,10.414,1.20269));
#792=CARTESIAN_POINT('',(31.75,10.44575,1.20269));
#793=CARTESIAN_POINT('',(31.75,10.4775,1.20269));
#794=CARTESIAN_POINT('',(31.75,10.541,1.20269));
#795=CARTESIAN_POINT('',(31.75,10.57275,1.20269));
#796=CARTESIAN_POINT('',(31.75,10.63625,1.20269));
#797=CARTESIAN_POINT('',(31.75,10.668,1.20269));
#798=CARTESIAN_POINT('',(31.75,10.7315,1.20269));
#799=CARTESIAN_POINT('',(31.75,10.76325,1.20269));
#800=CARTESIAN_POINT('',(31.75,10.82675,1.20269));
#801=CARTESIAN_POINT('',(31.75,10.8585,1.20269));
#802=CARTESIAN_POINT('',(31.75,10.922,1.20269));
#803=CARTESIAN_POINT('',(31.75,10.95375,1.20269));
#804=CARTESIAN_POINT('',(31.75,11.01725,1.20269));
#805=CARTESIAN_POINT('',(31.75,11.049,1.20269));
#806=CARTESIAN_POINT('',(31.75,11.1125,1.20269));
#807=CARTESIAN_POINT('',(31.75,11.14425,1.20269));
#808=CARTESIAN_POINT('',(31.75,11.20775,1.20269));
#809=CARTESIAN_POINT('',(31.75,11.2395,1.20269));
#810=CARTESIAN_POINT('',(31.75,11.303,1.20269));
#811=CARTESIAN_POINT('',(31.75,11.33475,1.20269));
#812=CARTESIAN_POINT('',(31.75,11.39825,1.20269));
#813=CARTESIAN_POINT('',(31.75,11.43,1.20269));
#814=CARTESIAN_POINT('',(31.75,11.4935,1.20269));
#815=CARTESIAN_POINT('',(31.75,11.52525,1.20269));
#816=CARTESIAN_POINT('',(31.75,11.58875,1.20269));
#817=CARTESIAN_POINT('',(31.75,11.6205,1.20269));
#818=CARTESIAN_POINT('',(31.75,11.684,1.20269));
#819=CARTESIAN_POINT('',(31.75,11.71575,1.20269));
#820=CARTESIAN_POINT('',(31.75,11.77925,1.20269));
#821=CARTESIAN_POINT('',(31.75,11.811,1.20269));
#822=CARTESIAN_POINT('',(31.75,11.8745,1.20269));
#823=CARTESIAN_POINT('',(31.75,11.90625,1.20269));
#824=CARTESIAN_POINT('',(31.75,11.96975,1.20269));
#825=CARTESIAN_POINT('',(31.75,12.0015,1.20269));
#826=CARTESIAN_POINT('',(31.75,12.065,1.20269));
#827=CARTESIAN_POINT('',(31.75,12.09675,1.20269));
#828=CARTESIAN_POINT('',(31.75,12.16025,1.20269));
#829=CARTESIAN_POINT('',(31.75,12.192,1.20269));
#830=CARTESIAN_POINT('',(31.75,12.2555,1.20269));
#831=CARTESIAN_POINT('',(31.75,12.28725,1.20269));
#832=CARTESIAN_POINT('',(31.75,12.35075,1.20269));
#833=CARTESIAN_POINT('',(31.75,12.3825,1.20269));
#834=CARTESIAN_POINT('',(31.75,12.446,1.20269));
#835=CARTESIAN_POINT('',(31.75,12.47775,1.20269));
#836=CARTESIAN_POINT('',(31.75,12.54125,1.20269));
#837=CARTESIAN_POINT('',(31.75,12.573,1.20269));
#838=CARTESIAN_POINT('',(31.75,12.6365,1.20269));
#839=CARTESIAN_POINT('',(31.75,12.66825,1.20269));
#840=CARTESIAN_POINT('',(31.75,12.73175,1.20269));
#841=CARTESIAN_POINT('',(31.75,12.7635,1.20269));
#842=CARTESIAN_POINT('',(31.75,12.827,1.20269));
#843=CARTESIAN_POINT('',(31.75,12.85875,1.20269));
#844=CARTESIAN_POINT('',(31.75,12.92225,1.20269));
#845=CARTESIAN_POINT('',(31.75,12.954,1.20269));
#846=CARTESIAN_POINT('',(31.75,13.0175,1.20269));
#847=CARTESIAN_POINT('',(31.75,13.04925,1.20269));
#848=CARTESIAN_POINT('',(31.75,13.11275,1.20269));
#849=CARTESIAN_POINT('',(31.75,13.1445,1.20269));
#850=CARTESIAN_POINT('',(31.75,13.208,1.20269));
#851=CARTESIAN_POINT('',(31.75,13.23975,1.20269));
#852=CARTESIAN_POINT('',(31.75,13.30325,1.20269));
#853=CARTESIAN_POINT('',(31.75,13.335,1.20269));
#854=CARTESIAN_POINT('',(31.75,13.3985,1.20269));
#855=CARTESIAN_POINT('',(31.75,13.43025,1.20269));
#856=CARTESIAN_POINT('',(31.75,13.462,1.20269));
#857=B_SPLINE_CURVE_WITH_KNOTS('',3,(#791,#792,#793,#794,#795,#796,#797,#798,#799,#800,#801,
#802,#803,#804,#805,#806,#807,#808,#809,#810,#811,#812,#813,#814,#815,#816,#817,#818,#819,#820,
#821,#822,#823,#824,#825,#826,#827,#828,#829,#830,#831,#832,#833,#834,#835,#836,#837,#838,#839,
#840,#841,#842,#843,#844,#845,#846,#847,#848,#849,#850,#851,#852,#853,#854,#855,#856),
.UNSPECIFIED.,.F.,.F.,(4,2,2,2,2,2,2,2,2,2,2,2,2,2,2,2,2,2,2,2,2,2,2,2,2,2,2,2,2,2,2,2,4),(0.,
0.0952499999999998,0.1905,0.28575,0.380999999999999,0.476249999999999,0.571499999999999,
0.666749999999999,0.761999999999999,0.857249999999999,0.9525,1.04775,1.143,1.23825,1.3335,
1.42875,1.524,1.61925,1.7145,1.80975,1.905,2.00025,2.0955,2.19075,2.286,2.38125,2.4765,2.57175,
2.667,2.76225,2.8575,2.95275,3.048),.UNSPECIFIED.);
#858=EDGE_CURVE('BSEAM448',#789,#69,#857,.T.);
#859=ORIENTED_EDGE('',*,*,#790,.F.);
#860=ORIENTED_EDGE('',*,*,#70,.T.);
#861=ORIENTED_EDGE('',*,*,#858,.T.);
#862=ORIENTED_EDGE('',*,*,#858,.F.);
#863=EDGE_LOOP('',(#859,#861,#860,#862));
#864=FACE_BOUND('',#863,.T.);
#865=ADVANCED_FACE('F448',(#864),#782,.F.);
#866=CARTESIAN_POINT('',(31.75,10.414,0.));
#867=DIRECTION('',(0.,1.,0.));
#868=DIRECTION('',(0.,0.,1.));
#869=AXIS2_PLACEMENT_3D('',#866,#867,#868);
#870=PLANE('',#869);
#871=ORIENTED_EDGE('',*,*,#790,.T.);
#872=EDGE_LOOP('',(#871));
#873=FACE_BOUND('',#872,.T.);
#874=ADVANCED_FACE('F444',(#873),#870,.T.);
#875=CARTESIAN_POINT('',(44.45,11.938,0.));
#876=DIRECTION('',(0.,1.,0.));
#877=DIRECTION('',(0.,0.,1.));
#878=AXIS2_PLACEMENT_3D('',#875,#876,#877);
#879=CYLINDRICAL_SURFACE('',#878,2.794);
#880=CARTESIAN_POINT('',(44.45,11.938,2.794));
#881=CARTESIAN_POINT('',(44.45,11.953875,2.794));
#882=CARTESIAN_POINT('',(44.45,11.96975,2.794));
#883=CARTESIAN_POINT('',(44.45,12.0015,2.794));
#884=CARTESIAN_POINT('',(44.45,12.017375,2.794));
#885=CARTESIAN_POINT('',(44.45,12.049125,2.794));
#886=CARTESIAN_POINT('',(44.45,12.065,2.794));
#887=CARTESIAN_POINT('',(44.45,12.09675,2.794));
#888=CARTESIAN_POINT('',(44.45,12.112625,2.794));
#889=CARTESIAN_POINT('',(44.45,12.144375,2.794));
#890=CARTESIAN_POINT('',(44.45,12.16025,2.794));
#891=CARTESIAN_POINT('',(44.45,12.192,2.794));
#892=CARTESIAN_POINT('',(44.45,12.207875,2.794));
#893=CARTESIAN_POINT('',(44.45,12.239625,2.794));
#894=CARTESIAN_POINT('',(44.45,12.2555,2.794));
#895=CARTESIAN_POINT('',(44.45,12.28725,2.794));
#896=CARTESIAN_POINT('',(44.45,12.303125,2.794));
#897=CARTESIAN_POINT('',(44.45,12.334875,2.794));
#898=CARTESIAN_POINT('',(44.45,12.35075,2.794));
#899=CARTESIAN_POINT('',(44.45,12.3825,2.794));
#900=CARTESIAN_POINT('',(44.45,12.398375,2.794));
#901=CARTESIAN_POINT('',(44.45,12.430125,2.794));
#902=CARTESIAN_POINT('',(44.45,12.446,2.794));
#903=CARTESIAN_POINT('',(44.45,12.47775,2.794));
#904=CARTESIAN_POINT('',(44.45,12.493625,2.794));
#905=CARTESIAN_POINT('',(44.45,12.525375,2.794));
#906=CARTESIAN_POINT('',(44.45,12.54125,2.794));
#907=CARTESIAN_POINT('',(44.45,12.573,2.794));
#908=CARTESIAN_POINT('',(44.45,12.588875,2.794));
#909=CARTESIAN_POINT('',(44.45,12.620625,2.794));
#910=CARTESIAN_POINT('',(44.45,12.6365,2.794));
#911=CARTESIAN_POINT('',(44.45,12.66825,2.794));
#912=CARTESIAN_POINT('',(44.45,12.684125,2.794));
#913=CARTESIAN_POINT('',(44.45,12.715875,2.794));
#914=CARTESIAN_POINT('',(44.45,12.73175,2.794));
#915=CARTESIAN_POINT('',(44.45,12.7635,2.794));
#916=CARTESIAN_POINT('',(44.45,12.779375,2.794));
#917=CARTESIAN_POINT('',(44.45,12.811125,2.794));
#918=CARTESIAN_POINT('',(44.45,12.827,2.794));
#919=CARTESIAN_POINT('',(44.45,12.85875,2.794));
#920=CARTESIAN_POINT('',(44.45,12.874625,2.794));
#921=CARTESIAN_POINT('',(44.45,12.906375,2.794));
#922=CARTESIAN_POINT('',(44.45,12.92225,2.794));
#923=CARTESIAN_POINT('',(44.45,12.954,2.794));
#924=CARTESIAN_POINT('',(44.45,12.969875,2.794));
#925=CARTESIAN_POINT('',(44.45,13.001625,2.794));
#926=CARTESIAN_POINT('',(44.45,13.0175,2.794));
#927=CARTESIAN_POINT('',(44.45,13.04925,2.794));
#928=CARTESIAN_POINT('',(44.45,13.065125,2.794));
#929=CARTESIAN_POINT('',(44.45,13.096875,2.794));
#930=CARTESIAN_POINT('',(44.45,13.11275,2.794));
#931=CARTESIAN_POINT('',(44.45,13.1445,2.794));
#932=CARTESIAN_POINT('',(44.45,13.160375,2.794));
#933=CARTESIAN_POINT('',(44.45,13.192125,2.794));
#934=CARTESIAN_POINT('',(44.45,13.208,2.794));
#935=CARTESIAN_POINT('',(44.45,13.23975,2.794));
#936=CARTESIAN_POINT('',(44.45,13.255625,2.794));
#937=CARTESIAN_POINT('',(44.45,13.287375,2.794));
#938=CARTESIAN_POINT('',(44.45,13.30325,2.794));
#939=CARTESIAN_POINT('',(44.45,13.335,2.794));
#940=CARTESIAN_POINT('',(44.45,13.350875,2.794));
#941=CARTESIAN_POINT('',(44.45,13.382625,2.794));
#942=CARTESIAN_POINT('',(44.45,13.3985,2.794));
#943=CARTESIAN_POINT('',(44.45,13.43025,2.794));
#944=CARTESIAN_POINT('',(44.45,13.446125,2.794));
#945=CARTESIAN_POINT('',(44.45,13.462,2.794));
#946=B_SPLINE_CURVE_WITH_KNOTS('',3,(#880,#881,#882,#883,#884,#885,#886,#887,#888,#889,#890,
#891,#892,#893,#894,#895,#896,#897,#898,#899,#900,#901,#902,#903,#904,#905,#906,#907,#908,#909,
#910,#911,#912,#913,#914,#915,#916,#917,#918,#919,#920,#921,#922,#923,#924,#925,#926,#927,#928,
#929,#930,#931,#932,#933,#934,#935,#936,#937,#938,#939,#940,#941,#942,#943,#944,#945),
.UNSPECIFIED.,.F.,.F.,(4,2,2,2,2,2,2,2,2,2,2,2,2,2,2,2,2,2,2,2,2,2,2,2,2,2,2,2,2,2,2,2,4),(0.,
0.0476250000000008,0.0952500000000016,0.142875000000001,0.190500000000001,0.238125,
0.285750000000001,0.333375,0.381000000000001,0.428625,0.476250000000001,0.523875,
0.571500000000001,0.619125,0.666750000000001,0.714375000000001,0.762000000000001,
0.809625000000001,0.85725,0.904875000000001,0.9525,1.000125,1.04775,1.095375,1.143,1.190625,
1.23825,1.285875,1.3335,1.381125,1.42875,1.476375,1.524),.UNSPECIFIED.);
#947=EDGE_CURVE('BSEAM441',#30,#58,#946,.T.);
#948=ORIENTED_EDGE('',*,*,#31,.F.);
#949=ORIENTED_EDGE('',*,*,#59,.T.);
#950=ORIENTED_EDGE('',*,*,#947,.T.);
#951=ORIENTED_EDGE('',*,*,#947,.F.);
#952=EDGE_LOOP('',(#948,#950,#949,#951));
#953=FACE_BOUND('',#952,.T.);
#954=ADVANCED_FACE('F441',(#953),#879,.F.);
#955=CARTESIAN_POINT('',(44.45,13.462,0.));
#956=DIRECTION('',(0.,-1.,0.));
#957=DIRECTION('',(0.,0.,-1.));
#958=AXIS2_PLACEMENT_3D('',#955,#956,#957);
#959=PLANE('',#958);
#960=DIRECTION('',(0.,0.,1.));
#961=VECTOR('',#960,1.);
#962=CARTESIAN_POINT('',(42.8625,13.462,-0.91654355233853));
#963=LINE('',#962,#961);
#964=CARTESIAN_POINT('',(42.8625,13.462,-0.91654355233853));
#965=VERTEX_POINT('',#964);
#966=CARTESIAN_POINT('',(42.8625,13.462,0.91654355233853));
#967=VERTEX_POINT('',#966);
#968=EDGE_CURVE('E213',#965,#967,#963,.T.);
#969=ORIENTED_EDGE('',*,*,#968,.F.);
#970=DIRECTION('',(-0.86602540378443,0.,0.500000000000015));
#971=VECTOR('',#970,1.);
#972=CARTESIAN_POINT('',(44.45,13.462,-1.8330871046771));
#973=LINE('',#972,#971);
#974=CARTESIAN_POINT('',(44.45,13.462,-1.8330871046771));
#975=VERTEX_POINT('',#974);
#976=EDGE_CURVE('E50',#975,#965,#973,.T.);
#977=ORIENTED_EDGE('',*,*,#976,.F.);
#978=DIRECTION('',(-0.866025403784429,0.,-0.500000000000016));
#979=VECTOR('',#978,1.);
#980=CARTESIAN_POINT('',(46.0375,13.462,-0.91654355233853));
#981=LINE('',#980,#979);
#982=CARTESIAN_POINT('',(46.0375,13.462,-0.91654355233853));
#983=VERTEX_POINT('',#982);
#984=EDGE_CURVE('E199',#983,#975,#981,.T.);
#985=ORIENTED_EDGE('',*,*,#984,.F.);
#986=DIRECTION('',(0.,0.,-1.));
#987=VECTOR('',#986,1.);
#988=CARTESIAN_POINT('',(46.0375,13.462,0.91654355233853));
#989=LINE('',#988,#987);
#990=CARTESIAN_POINT('',(46.0375,13.462,0.91654355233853));
#991=VERTEX_POINT('',#990);
#992=EDGE_CURVE('E202',#991,#983,#989,.T.);
#993=ORIENTED_EDGE('',*,*,#992,.F.);
#994=DIRECTION('',(0.866025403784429,0.,-0.500000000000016));
#995=VECTOR('',#994,1.);
#996=CARTESIAN_POINT('',(44.45,13.462,1.8330871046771));
#997=LINE('',#996,#995);
#998=CARTESIAN_POINT('',(44.45,13.462,1.8330871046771));
#999=VERTEX_POINT('',#998);
#1000=EDGE_CURVE('E218',#999,#991,#997,.T.);
#1001=ORIENTED_EDGE('',*,*,#1000,.F.);
#1002=DIRECTION('',(0.86602540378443,0.,0.500000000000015));
#1003=VECTOR('',#1002,1.);
#1004=CARTESIAN_POINT('',(42.8625,13.462,0.91654355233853));
#1005=LINE('',#1004,#1003);
#1006=EDGE_CURVE('E215',#967,#999,#1005,.T.);
#1007=ORIENTED_EDGE('',*,*,#1006,.F.);
#1008=EDGE_LOOP('',(#969,#977,#985,#993,#1001,#1007));
#1009=FACE_BOUND('',#1008,.T.);
#1010=CARTESIAN_POINT('',(44.45,13.462,0.));
#1011=DIRECTION('',(0.,1.,0.));
#1012=DIRECTION('',(0.,0.,1.));
#1013=AXIS2_PLACEMENT_3D('',#1010,#1011,#1012);
#1014=CIRCLE('',#1013,2.032);
#1015=CARTESIAN_POINT('',(44.45,13.462,2.032));
#1016=VERTEX_POINT('',#1015);
#1017=EDGE_CURVE('E238',#1016,#1016,#1014,.T.);
#1018=ORIENTED_EDGE('',*,*,#1017,.T.);
#1019=EDGE_LOOP('',(#1018));
#1020=FACE_BOUND('',#1019,.T.);
#1021=ADVANCED_FACE('F439',(#1009,#1020),#959,.F.);
#1022=CARTESIAN_POINT('',(44.45,12.9540000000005,0.));
#1023=DIRECTION('',(0.,1.,0.));
#1024=DIRECTION('',(0.,0.,1.));
#1025=AXIS2_PLACEMENT_3D('',#1022,#1023,#1024);
#1026=TOROIDAL_SURFACE('',#1025,2.03200000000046,0.507999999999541);
#1027=ORIENTED_EDGE('',*,*,#1017,.F.);
#1028=EDGE_LOOP('',(#1027));
#1029=FACE_BOUND('',#1028,.T.);
#1030=CARTESIAN_POINT('',(44.45,12.954,0.));
#1031=DIRECTION('',(0.,1.,0.));
#1032=DIRECTION('',(0.,0.,1.));
#1033=AXIS2_PLACEMENT_3D('',#1030,#1031,#1032);
#1034=CIRCLE('',#1033,2.54);
#1035=CARTESIAN_POINT('',(44.45,12.954,2.54));
#1036=VERTEX_POINT('',#1035);
#1037=EDGE_CURVE('E235',#1036,#1036,#1034,.T.);
#1038=ORIENTED_EDGE('',*,*,#1037,.T.);
#1039=EDGE_LOOP('',(#1038));
#1040=FACE_BOUND('',#1039,.T.);
#1041=ADVANCED_FACE('F585',(#1029,#1040),#1026,.T.);
#1042=CARTESIAN_POINT('',(44.45,11.938,0.));
#1043=DIRECTION('',(0.,1.,0.));
#1044=DIRECTION('',(0.,0.,1.));
#1045=AXIS2_PLACEMENT_3D('',#1042,#1043,#1044);
#1046=CYLINDRICAL_SURFACE('',#1045,2.54);
#1047=ORIENTED_EDGE('',*,*,#1037,.F.);
#1048=EDGE_LOOP('',(#1047));
#1049=FACE_BOUND('',#1048,.T.);
#1050=ORIENTED_EDGE('',*,*,#42,.T.);
#1051=EDGE_LOOP('',(#1050));
#1052=FACE_BOUND('',#1051,.T.);
#1053=ADVANCED_FACE('F590',(#1049,#1052),#1046,.T.);
#1054=CARTESIAN_POINT('',(44.45,12.7,-1.8330871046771));
#1055=DIRECTION('',(-0.500000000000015,0.,-0.86602540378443));
#1056=DIRECTION('',(-0.86602540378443,0.,0.500000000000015));
#1057=AXIS2_PLACEMENT_3D('',#1054,#1055,#1056);
#1058=PLANE('',#1057);
#1059=ORIENTED_EDGE('',*,*,#976,.T.);
#1060=DIRECTION('',(0.,1.,0.));
#1061=VECTOR('',#1060,1.);
#1062=CARTESIAN_POINT('',(42.8625,12.7,-0.91654355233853));
#1063=LINE('',#1062,#1061);
#1064=CARTESIAN_POINT('',(42.8625,12.7,-0.91654355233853));
#1065=VERTEX_POINT('',#1064);
#1066=EDGE_CURVE('E176',#1065,#965,#1063,.T.);
#1067=ORIENTED_EDGE('',*,*,#1066,.F.);
#1068=DIRECTION('',(-0.86602540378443,0.,0.500000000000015));
#1069=VECTOR('',#1068,1.);
#1070=CARTESIAN_POINT('',(44.45,12.7,-1.8330871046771));
#1071=LINE('',#1070,#1069);
#1072=CARTESIAN_POINT('',(44.45,12.7,-1.8330871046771));
#1073=VERTEX_POINT('',#1072);
#1074=EDGE_CURVE('E180',#1073,#1065,#1071,.T.);
#1075=ORIENTED_EDGE('',*,*,#1074,.F.);
#1076=DIRECTION('',(0.,1.,0.));
#1077=VECTOR('',#1076,1.);
#1078=CARTESIAN_POINT('',(44.45,12.7,-1.8330871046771));
#1079=LINE('',#1078,#1077);
#1080=EDGE_CURVE('E223',#1073,#975,#1079,.T.);
#1081=ORIENTED_EDGE('',*,*,#1080,.T.);
#1082=EDGE_LOOP('',(#1059,#1067,#1075,#1081));
#1083=FACE_BOUND('',#1082,.T.);
#1084=ADVANCED_FACE('F178',(#1083),#1058,.F.);
#1085=CARTESIAN_POINT('',(46.0375,12.7,-0.91654355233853));
#1086=DIRECTION('',(0.500000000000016,0.,-0.866025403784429));
#1087=DIRECTION('',(-0.866025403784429,0.,-0.500000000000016));
#1088=AXIS2_PLACEMENT_3D('',#1085,#1086,#1087);
#1089=PLANE('',#1088);
#1090=ORIENTED_EDGE('',*,*,#984,.T.);
#1091=ORIENTED_EDGE('',*,*,#1080,.F.);
#1092=DIRECTION('',(-0.866025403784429,0.,-0.500000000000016));
#1093=VECTOR('',#1092,1.);
#1094=CARTESIAN_POINT('',(46.0375,12.7,-0.91654355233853));
#1095=LINE('',#1094,#1093);
#1096=CARTESIAN_POINT('',(46.0375,12.7,-0.91654355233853));
#1097=VERTEX_POINT('',#1096);
#1098=EDGE_CURVE('E186',#1097,#1073,#1095,.T.);
#1099=ORIENTED_EDGE('',*,*,#1098,.F.);
#1100=DIRECTION('',(0.,1.,0.));
#1101=VECTOR('',#1100,1.);
#1102=CARTESIAN_POINT('',(46.0375,12.7,-0.91654355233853));
#1103=LINE('',#1102,#1101);
#1104=EDGE_CURVE('E226',#1097,#983,#1103,.T.);
#1105=ORIENTED_EDGE('',*,*,#1104,.T.);
#1106=EDGE_LOOP('',(#1090,#1091,#1099,#1105));
#1107=FACE_BOUND('',#1106,.T.);
#1108=ADVANCED_FACE('F614',(#1107),#1089,.F.);
#1109=CARTESIAN_POINT('',(46.0375,12.7,0.91654355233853));
#1110=DIRECTION('',(1.,0.,0.));
#1111=DIRECTION('',(0.,0.,-1.));
#1112=AXIS2_PLACEMENT_3D('',#1109,#1110,#1111);
#1113=PLANE('',#1112);
#1114=ORIENTED_EDGE('',*,*,#992,.T.);
#1115=ORIENTED_EDGE('',*,*,#1104,.F.);
#1116=DIRECTION('',(0.,0.,-1.));
#1117=VECTOR('',#1116,1.);
#1118=CARTESIAN_POINT('',(46.0375,12.7,0.91654355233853));
#1119=LINE('',#1118,#1117);
#1120=CARTESIAN_POINT('',(46.0375,12.7,0.91654355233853));
#1121=VERTEX_POINT('',#1120);
#1122=EDGE_CURVE('E209',#1121,#1097,#1119,.T.);
#1123=ORIENTED_EDGE('',*,*,#1122,.F.);
#1124=DIRECTION('',(0.,1.,0.));
#1125=VECTOR('',#1124,1.);
#1126=CARTESIAN_POINT('',(46.0375,12.7,0.91654355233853));
#1127=LINE('',#1126,#1125);
#1128=EDGE_CURVE('E228',#1121,#991,#1127,.T.);
#1129=ORIENTED_EDGE('',*,*,#1128,.T.);
#1130=EDGE_LOOP('',(#1114,#1115,#1123,#1129));
#1131=FACE_BOUND('',#1130,.T.);
#1132=ADVANCED_FACE('F623',(#1131),#1113,.F.);
#1133=CARTESIAN_POINT('',(44.45,12.7,1.8330871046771));
#1134=DIRECTION('',(0.500000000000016,0.,0.866025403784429));
#1135=DIRECTION('',(0.866025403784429,0.,-0.500000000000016));
#1136=AXIS2_PLACEMENT_3D('',#1133,#1134,#1135);
#1137=PLANE('',#1136);
#1138=ORIENTED_EDGE('',*,*,#1000,.T.);
#1139=ORIENTED_EDGE('',*,*,#1128,.F.);
#1140=DIRECTION('',(0.866025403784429,0.,-0.500000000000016));
#1141=VECTOR('',#1140,1.);
#1142=CARTESIAN_POINT('',(44.45,12.7,1.8330871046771));
#1143=LINE('',#1142,#1141);
#1144=CARTESIAN_POINT('',(44.45,12.7,1.8330871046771));
#1145=VERTEX_POINT('',#1144);
#1146=EDGE_CURVE('E206',#1145,#1121,#1143,.T.);
#1147=ORIENTED_EDGE('',*,*,#1146,.F.);
#1148=DIRECTION('',(0.,1.,0.));
#1149=VECTOR('',#1148,1.);
#1150=CARTESIAN_POINT('',(44.45,12.7,1.8330871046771));
#1151=LINE('',#1150,#1149);
#1152=EDGE_CURVE('E230',#1145,#999,#1151,.T.);
#1153=ORIENTED_EDGE('',*,*,#1152,.T.);
#1154=EDGE_LOOP('',(#1138,#1139,#1147,#1153));
#1155=FACE_BOUND('',#1154,.T.);
#1156=ADVANCED_FACE('F633',(#1155),#1137,.F.);
#1157=CARTESIAN_POINT('',(42.8625,12.7,0.91654355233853));
#1158=DIRECTION('',(-0.500000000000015,0.,0.86602540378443));
#1159=DIRECTION('',(0.86602540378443,0.,0.500000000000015));
#1160=AXIS2_PLACEMENT_3D('',#1157,#1158,#1159);
#1161=PLANE('',#1160);
#1162=ORIENTED_EDGE('',*,*,#1006,.T.);
#1163=ORIENTED_EDGE('',*,*,#1152,.F.);
#1164=DIRECTION('',(0.86602540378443,0.,0.500000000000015));
#1165=VECTOR('',#1164,1.);
#1166=CARTESIAN_POINT('',(42.8625,12.7,0.91654355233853));
#1167=LINE('',#1166,#1165);
#1168=CARTESIAN_POINT('',(42.8625,12.7,0.91654355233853));
#1169=VERTEX_POINT('',#1168);
#1170=EDGE_CURVE('E194',#1169,#1145,#1167,.T.);
#1171=ORIENTED_EDGE('',*,*,#1170,.F.);
#1172=DIRECTION('',(0.,1.,0.));
#1173=VECTOR('',#1172,1.);
#1174=CARTESIAN_POINT('',(42.8625,12.7,0.91654355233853));
#1175=LINE('',#1174,#1173);
#1176=EDGE_CURVE('E185',#1169,#967,#1175,.T.);
#1177=ORIENTED_EDGE('',*,*,#1176,.T.);
#1178=EDGE_LOOP('',(#1162,#1163,#1171,#1177));
#1179=FACE_BOUND('',#1178,.T.);
#1180=ADVANCED_FACE('F643',(#1179),#1161,.F.);
#1181=CARTESIAN_POINT('',(42.8625,12.7,-0.91654355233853));
#1182=DIRECTION('',(-1.,0.,0.));
#1183=DIRECTION('',(0.,0.,1.));
#1184=AXIS2_PLACEMENT_3D('',#1181,#1182,#1183);
#1185=PLANE('',#1184);
#1186=ORIENTED_EDGE('',*,*,#968,.T.);
#1187=ORIENTED_EDGE('',*,*,#1176,.F.);
#1188=DIRECTION('',(0.,0.,1.));
#1189=VECTOR('',#1188,1.);
#1190=CARTESIAN_POINT('',(42.8625,12.7,-0.91654355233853));
#1191=LINE('',#1190,#1189);
#1192=EDGE_CURVE('E189',#1065,#1169,#1191,.T.);
#1193=ORIENTED_EDGE('',*,*,#1192,.F.);
#1194=ORIENTED_EDGE('',*,*,#1066,.T.);
#1195=EDGE_LOOP('',(#1186,#1187,#1193,#1194));
#1196=FACE_BOUND('',#1195,.T.);
#1197=ADVANCED_FACE('F190',(#1196),#1185,.F.);
#1198=CARTESIAN_POINT('',(44.45,12.7,-1.8330871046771));
#1199=DIRECTION('',(0.,-1.,0.));
#1200=DIRECTION('',(0.,0.,-1.));
#1201=AXIS2_PLACEMENT_3D('',#1198,#1199,#1200);
#1202=PLANE('',#1201);
#1203=ORIENTED_EDGE('',*,*,#1074,.T.);
#1204=ORIENTED_EDGE('',*,*,#1192,.T.);
#1205=ORIENTED_EDGE('',*,*,#1170,.T.);
#1206=ORIENTED_EDGE('',*,*,#1146,.T.);
#1207=ORIENTED_EDGE('',*,*,#1122,.T.);
#1208=ORIENTED_EDGE('',*,*,#1098,.T.);
#1209=EDGE_LOOP('',(#1203,#1204,#1205,#1206,#1207,#1208));
#1210=FACE_BOUND('',#1209,.T.);
#1211=ADVANCED_FACE('F196',(#1210),#1202,.F.);
#1212=CLOSED_SHELL('',(#46,#141,#181,#212,#252,#283,#314,#345,#392,#423,#454,#483,#514,#531,
#538,#558,#574,#594,#614,#627,#647,#667,#680,#768,#777,#865,#874,#954,#1021,#1041,#1053,#1084,
#1108,#1132,#1156,#1180,#1197,#1211));
#1213=MANIFOLD_SOLID_BREP('B2',#1212);
#1214=ADVANCED_BREP_SHAPE_REPRESENTATION('',(#18,#1213),#14);
#1215=SHAPE_DEFINITION_REPRESENTATION(#9,#1214);
ENDSEC;
END-ISO-10303-21;
